VERSION 5.7 ;
  NOWIREEXTENSIONATPIN ON ;
  DIVIDERCHAR "/" ;
  BUSBITCHARS "[]" ;
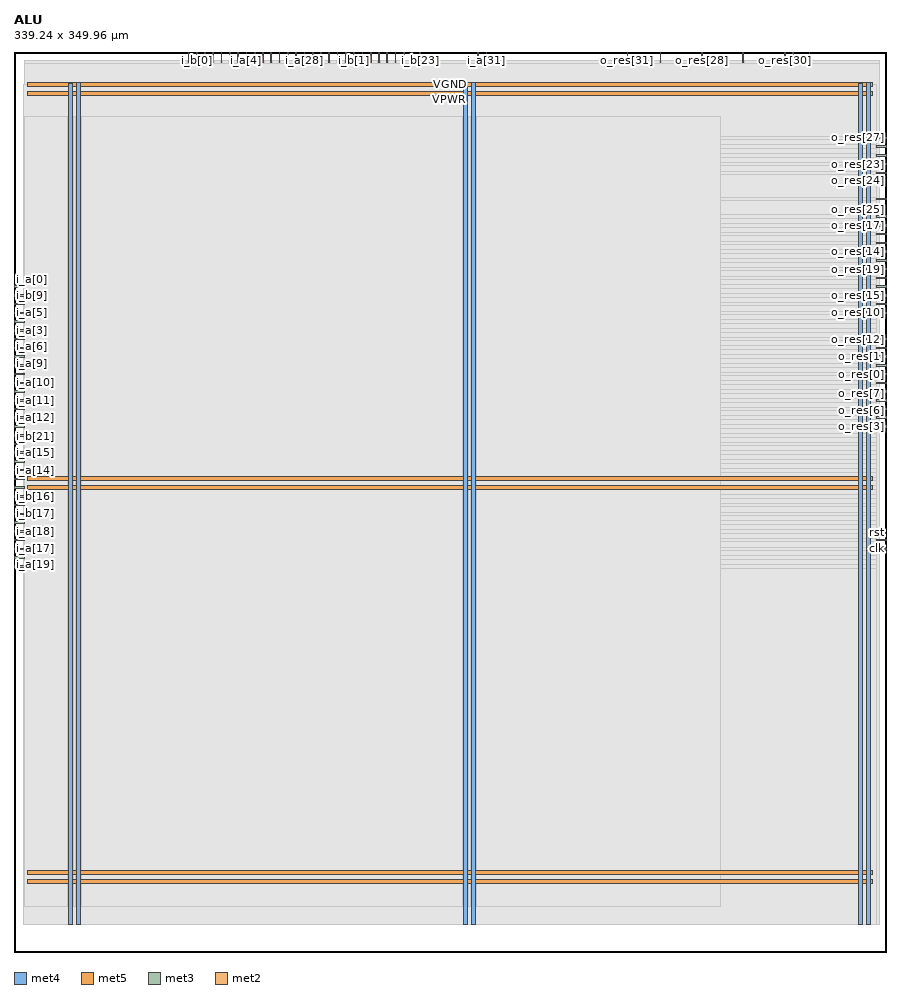
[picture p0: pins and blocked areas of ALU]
MACRO ALU
  CLASS BLOCK ;
  FOREIGN ALU ;
  ORIGIN 0.000 0.000 ;
  SIZE 339.240 BY 349.960 ;
  PIN VGND
    DIRECTION INOUT ;
    USE GROUND ;
    PORT
      LAYER met4 ;
        RECT 24.340 10.640 25.940 337.990 ;
    END
    PORT
      LAYER met4 ;
        RECT 177.940 10.640 179.540 337.990 ;
    END
    PORT
      LAYER met4 ;
        RECT 331.540 10.640 333.140 337.990 ;
    END
    PORT
      LAYER met5 ;
        RECT 5.280 30.030 333.740 31.630 ;
    END
    PORT
      LAYER met5 ;
        RECT 5.280 183.210 333.740 184.810 ;
    END
    PORT
      LAYER met5 ;
        RECT 5.280 336.390 333.740 337.990 ;
    END
  END VGND
  PIN VPWR
    DIRECTION INOUT ;
    USE POWER ;
    PORT
      LAYER met4 ;
        RECT 21.040 10.640 22.640 337.520 ;
    END
    PORT
      LAYER met4 ;
        RECT 174.640 10.640 176.240 337.520 ;
    END
    PORT
      LAYER met4 ;
        RECT 328.240 10.640 329.840 337.520 ;
    END
    PORT
      LAYER met5 ;
        RECT 5.280 26.730 333.740 28.330 ;
    END
    PORT
      LAYER met5 ;
        RECT 5.280 179.910 333.740 181.510 ;
    END
    PORT
      LAYER met5 ;
        RECT 5.280 333.090 333.740 334.690 ;
    END
  END VPWR
  PIN clk
    DIRECTION INPUT ;
    USE SIGNAL ;
    ANTENNAGATEAREA 0.852000 ;
    PORT
      LAYER met3 ;
        RECT 335.240 156.440 339.240 157.040 ;
    END
  END clk
  PIN i_a[0]
    DIRECTION INPUT ;
    USE SIGNAL ;
    ANTENNAGATEAREA 0.196500 ;
    PORT
      LAYER met3 ;
        RECT 0.000 258.440 4.000 259.040 ;
    END
  END i_a[0]
  PIN i_a[10]
    DIRECTION INPUT ;
    USE SIGNAL ;
    ANTENNAGATEAREA 0.196500 ;
    PORT
      LAYER met3 ;
        RECT 0.000 221.040 4.000 221.640 ;
    END
  END i_a[10]
  PIN i_a[11]
    DIRECTION INPUT ;
    USE SIGNAL ;
    ANTENNAGATEAREA 0.196500 ;
    PORT
      LAYER met3 ;
        RECT 0.000 214.240 4.000 214.840 ;
    END
  END i_a[11]
  PIN i_a[12]
    DIRECTION INPUT ;
    USE SIGNAL ;
    ANTENNAGATEAREA 0.196500 ;
    PORT
      LAYER met3 ;
        RECT 0.000 207.440 4.000 208.040 ;
    END
  END i_a[12]
  PIN i_a[13]
    DIRECTION INPUT ;
    USE SIGNAL ;
    ANTENNAGATEAREA 0.196500 ;
    PORT
      LAYER met3 ;
        RECT 0.000 200.640 4.000 201.240 ;
    END
  END i_a[13]
  PIN i_a[14]
    DIRECTION INPUT ;
    USE SIGNAL ;
    ANTENNAGATEAREA 0.196500 ;
    PORT
      LAYER met3 ;
        RECT 0.000 187.040 4.000 187.640 ;
    END
  END i_a[14]
  PIN i_a[15]
    DIRECTION INPUT ;
    USE SIGNAL ;
    ANTENNAGATEAREA 0.196500 ;
    PORT
      LAYER met3 ;
        RECT 0.000 193.840 4.000 194.440 ;
    END
  END i_a[15]
  PIN i_a[16]
    DIRECTION INPUT ;
    USE SIGNAL ;
    ANTENNAGATEAREA 0.196500 ;
    PORT
      LAYER met3 ;
        RECT 0.000 149.640 4.000 150.240 ;
    END
  END i_a[16]
  PIN i_a[17]
    DIRECTION INPUT ;
    USE SIGNAL ;
    ANTENNAGATEAREA 0.196500 ;
    PORT
      LAYER met3 ;
        RECT 0.000 156.440 4.000 157.040 ;
    END
  END i_a[17]
  PIN i_a[18]
    DIRECTION INPUT ;
    USE SIGNAL ;
    ANTENNAGATEAREA 0.196500 ;
    PORT
      LAYER met3 ;
        RECT 0.000 163.240 4.000 163.840 ;
    END
  END i_a[18]
  PIN i_a[19]
    DIRECTION INPUT ;
    USE SIGNAL ;
    ANTENNAGATEAREA 0.196500 ;
    PORT
      LAYER met3 ;
        RECT 0.000 153.040 4.000 153.640 ;
    END
  END i_a[19]
  PIN i_a[1]
    DIRECTION INPUT ;
    USE SIGNAL ;
    ANTENNAGATEAREA 0.196500 ;
    PORT
      LAYER met2 ;
        RECT 67.710 345.960 67.990 349.960 ;
    END
  END i_a[1]
  PIN i_a[20]
    DIRECTION INPUT ;
    USE SIGNAL ;
    ANTENNAGATEAREA 0.196500 ;
    PORT
      LAYER met3 ;
        RECT 0.000 183.640 4.000 184.240 ;
    END
  END i_a[20]
  PIN i_a[21]
    DIRECTION INPUT ;
    USE SIGNAL ;
    ANTENNAGATEAREA 0.196500 ;
    PORT
      LAYER met3 ;
        RECT 0.000 166.640 4.000 167.240 ;
    END
  END i_a[21]
  PIN i_a[22]
    DIRECTION INPUT ;
    USE SIGNAL ;
    ANTENNAGATEAREA 0.196500 ;
    PORT
      LAYER met3 ;
        RECT 0.000 159.840 4.000 160.440 ;
    END
  END i_a[22]
  PIN i_a[23]
    DIRECTION INPUT ;
    USE SIGNAL ;
    ANTENNAGATEAREA 0.196500 ;
    PORT
      LAYER met2 ;
        RECT 125.670 345.960 125.950 349.960 ;
    END
  END i_a[23]
  PIN i_a[24]
    DIRECTION INPUT ;
    USE SIGNAL ;
    ANTENNAGATEAREA 0.196500 ;
    PORT
      LAYER met2 ;
        RECT 122.450 345.960 122.730 349.960 ;
    END
  END i_a[24]
  PIN i_a[25]
    DIRECTION INPUT ;
    USE SIGNAL ;
    ANTENNAGATEAREA 0.196500 ;
    PORT
      LAYER met2 ;
        RECT 109.570 345.960 109.850 349.960 ;
    END
  END i_a[25]
  PIN i_a[26]
    DIRECTION INPUT ;
    USE SIGNAL ;
    ANTENNAGATEAREA 0.196500 ;
    PORT
      LAYER met2 ;
        RECT 119.230 345.960 119.510 349.960 ;
    END
  END i_a[26]
  PIN i_a[27]
    DIRECTION INPUT ;
    USE SIGNAL ;
    ANTENNAGATEAREA 0.196500 ;
    PORT
      LAYER met2 ;
        RECT 103.130 345.960 103.410 349.960 ;
    END
  END i_a[27]
  PIN i_a[28]
    DIRECTION INPUT ;
    USE SIGNAL ;
    ANTENNAGATEAREA 0.196500 ;
    PORT
      LAYER met2 ;
        RECT 112.790 345.960 113.070 349.960 ;
    END
  END i_a[28]
  PIN i_a[29]
    DIRECTION INPUT ;
    USE SIGNAL ;
    ANTENNAGATEAREA 0.196500 ;
    PORT
      LAYER met2 ;
        RECT 128.890 345.960 129.170 349.960 ;
    END
  END i_a[29]
  PIN i_a[2]
    DIRECTION INPUT ;
    USE SIGNAL ;
    ANTENNAGATEAREA 0.196500 ;
    PORT
      LAYER met2 ;
        RECT 83.810 345.960 84.090 349.960 ;
    END
  END i_a[2]
  PIN i_a[30]
    DIRECTION INPUT ;
    USE SIGNAL ;
    ANTENNAGATEAREA 0.196500 ;
    PORT
      LAYER met2 ;
        RECT 116.010 345.960 116.290 349.960 ;
    END
  END i_a[30]
  PIN i_a[31]
    DIRECTION INPUT ;
    USE SIGNAL ;
    ANTENNAGATEAREA 0.196500 ;
    PORT
      LAYER met2 ;
        RECT 183.630 345.960 183.910 349.960 ;
    END
  END i_a[31]
  PIN i_a[3]
    DIRECTION INPUT ;
    USE SIGNAL ;
    ANTENNAGATEAREA 0.196500 ;
    PORT
      LAYER met3 ;
        RECT 0.000 241.440 4.000 242.040 ;
    END
  END i_a[3]
  PIN i_a[4]
    DIRECTION INPUT ;
    USE SIGNAL ;
    ANTENNAGATEAREA 0.196500 ;
    PORT
      LAYER met2 ;
        RECT 90.250 345.960 90.530 349.960 ;
    END
  END i_a[4]
  PIN i_a[5]
    DIRECTION INPUT ;
    USE SIGNAL ;
    ANTENNAGATEAREA 0.196500 ;
    PORT
      LAYER met3 ;
        RECT 0.000 248.240 4.000 248.840 ;
    END
  END i_a[5]
  PIN i_a[6]
    DIRECTION INPUT ;
    USE SIGNAL ;
    ANTENNAGATEAREA 0.196500 ;
    PORT
      LAYER met3 ;
        RECT 0.000 238.040 4.000 238.640 ;
    END
  END i_a[6]
  PIN i_a[7]
    DIRECTION INPUT ;
    USE SIGNAL ;
    ANTENNAGATEAREA 0.196500 ;
    PORT
      LAYER met2 ;
        RECT 87.030 345.960 87.310 349.960 ;
    END
  END i_a[7]
  PIN i_a[8]
    DIRECTION INPUT ;
    USE SIGNAL ;
    ANTENNAGATEAREA 0.196500 ;
    PORT
      LAYER met3 ;
        RECT 0.000 234.640 4.000 235.240 ;
    END
  END i_a[8]
  PIN i_a[9]
    DIRECTION INPUT ;
    USE SIGNAL ;
    ANTENNAGATEAREA 0.196500 ;
    PORT
      LAYER met3 ;
        RECT 0.000 231.240 4.000 231.840 ;
    END
  END i_a[9]
  PIN i_b[0]
    DIRECTION INPUT ;
    USE SIGNAL ;
    ANTENNAGATEAREA 0.196500 ;
    PORT
      LAYER met2 ;
        RECT 70.930 345.960 71.210 349.960 ;
    END
  END i_b[0]
  PIN i_b[10]
    DIRECTION INPUT ;
    USE SIGNAL ;
    ANTENNAGATEAREA 0.196500 ;
    PORT
      LAYER met3 ;
        RECT 0.000 251.640 4.000 252.240 ;
    END
  END i_b[10]
  PIN i_b[11]
    DIRECTION INPUT ;
    USE SIGNAL ;
    ANTENNAGATEAREA 0.196500 ;
    PORT
      LAYER met3 ;
        RECT 0.000 244.840 4.000 245.440 ;
    END
  END i_b[11]
  PIN i_b[12]
    DIRECTION INPUT ;
    USE SIGNAL ;
    ANTENNAGATEAREA 0.196500 ;
    PORT
      LAYER met3 ;
        RECT 0.000 227.840 4.000 228.440 ;
    END
  END i_b[12]
  PIN i_b[13]
    DIRECTION INPUT ;
    USE SIGNAL ;
    ANTENNAGATEAREA 0.196500 ;
    PORT
      LAYER met3 ;
        RECT 0.000 224.440 4.000 225.040 ;
    END
  END i_b[13]
  PIN i_b[14]
    DIRECTION INPUT ;
    USE SIGNAL ;
    ANTENNAGATEAREA 0.196500 ;
    PORT
      LAYER met3 ;
        RECT 0.000 210.840 4.000 211.440 ;
    END
  END i_b[14]
  PIN i_b[15]
    DIRECTION INPUT ;
    USE SIGNAL ;
    ANTENNAGATEAREA 0.196500 ;
    PORT
      LAYER met3 ;
        RECT 0.000 217.640 4.000 218.240 ;
    END
  END i_b[15]
  PIN i_b[16]
    DIRECTION INPUT ;
    USE SIGNAL ;
    ANTENNAGATEAREA 0.196500 ;
    PORT
      LAYER met3 ;
        RECT 0.000 176.840 4.000 177.440 ;
    END
  END i_b[16]
  PIN i_b[17]
    DIRECTION INPUT ;
    USE SIGNAL ;
    ANTENNAGATEAREA 0.196500 ;
    PORT
      LAYER met3 ;
        RECT 0.000 170.040 4.000 170.640 ;
    END
  END i_b[17]
  PIN i_b[18]
    DIRECTION INPUT ;
    USE SIGNAL ;
    ANTENNAGATEAREA 0.196500 ;
    PORT
      LAYER met3 ;
        RECT 0.000 173.440 4.000 174.040 ;
    END
  END i_b[18]
  PIN i_b[19]
    DIRECTION INPUT ;
    USE SIGNAL ;
    ANTENNAGATEAREA 0.196500 ;
    PORT
      LAYER met3 ;
        RECT 0.000 180.240 4.000 180.840 ;
    END
  END i_b[19]
  PIN i_b[1]
    DIRECTION INPUT ;
    USE SIGNAL ;
    ANTENNAGATEAREA 0.196500 ;
    PORT
      LAYER met2 ;
        RECT 132.110 345.960 132.390 349.960 ;
    END
  END i_b[1]
  PIN i_b[20]
    DIRECTION INPUT ;
    USE SIGNAL ;
    ANTENNAGATEAREA 0.196500 ;
    PORT
      LAYER met3 ;
        RECT 0.000 190.440 4.000 191.040 ;
    END
  END i_b[20]
  PIN i_b[21]
    DIRECTION INPUT ;
    USE SIGNAL ;
    ANTENNAGATEAREA 0.196500 ;
    PORT
      LAYER met3 ;
        RECT 0.000 197.240 4.000 197.840 ;
    END
  END i_b[21]
  PIN i_b[22]
    DIRECTION INPUT ;
    USE SIGNAL ;
    ANTENNAGATEAREA 0.196500 ;
    PORT
      LAYER met3 ;
        RECT 0.000 204.040 4.000 204.640 ;
    END
  END i_b[22]
  PIN i_b[23]
    DIRECTION INPUT ;
    USE SIGNAL ;
    ANTENNAGATEAREA 0.196500 ;
    PORT
      LAYER met2 ;
        RECT 157.870 345.960 158.150 349.960 ;
    END
  END i_b[23]
  PIN i_b[24]
    DIRECTION INPUT ;
    USE SIGNAL ;
    ANTENNAGATEAREA 0.196500 ;
    PORT
      LAYER met2 ;
        RECT 151.430 345.960 151.710 349.960 ;
    END
  END i_b[24]
  PIN i_b[25]
    DIRECTION INPUT ;
    USE SIGNAL ;
    ANTENNAGATEAREA 0.196500 ;
    PORT
      LAYER met2 ;
        RECT 135.330 345.960 135.610 349.960 ;
    END
  END i_b[25]
  PIN i_b[26]
    DIRECTION INPUT ;
    USE SIGNAL ;
    ANTENNAGATEAREA 0.196500 ;
    PORT
      LAYER met2 ;
        RECT 148.210 345.960 148.490 349.960 ;
    END
  END i_b[26]
  PIN i_b[27]
    DIRECTION INPUT ;
    USE SIGNAL ;
    ANTENNAGATEAREA 0.196500 ;
    PORT
      LAYER met2 ;
        RECT 138.550 345.960 138.830 349.960 ;
    END
  END i_b[27]
  PIN i_b[28]
    DIRECTION INPUT ;
    USE SIGNAL ;
    ANTENNAGATEAREA 0.196500 ;
    PORT
      LAYER met2 ;
        RECT 154.650 345.960 154.930 349.960 ;
    END
  END i_b[28]
  PIN i_b[29]
    DIRECTION INPUT ;
    USE SIGNAL ;
    ANTENNAGATEAREA 0.196500 ;
    PORT
      LAYER met2 ;
        RECT 141.770 345.960 142.050 349.960 ;
    END
  END i_b[29]
  PIN i_b[2]
    DIRECTION INPUT ;
    USE SIGNAL ;
    ANTENNAGATEAREA 0.196500 ;
    PORT
      LAYER met2 ;
        RECT 106.350 345.960 106.630 349.960 ;
    END
  END i_b[2]
  PIN i_b[30]
    DIRECTION INPUT ;
    USE SIGNAL ;
    ANTENNAGATEAREA 0.196500 ;
    PORT
      LAYER met2 ;
        RECT 144.990 345.960 145.270 349.960 ;
    END
  END i_b[30]
  PIN i_b[31]
    DIRECTION INPUT ;
    USE SIGNAL ;
    ANTENNAGATEAREA 0.196500 ;
    PORT
      LAYER met2 ;
        RECT 180.410 345.960 180.690 349.960 ;
    END
  END i_b[31]
  PIN i_b[3]
    DIRECTION INPUT ;
    USE SIGNAL ;
    ANTENNAGATEAREA 0.196500 ;
    PORT
      LAYER met2 ;
        RECT 74.150 345.960 74.430 349.960 ;
    END
  END i_b[3]
  PIN i_b[4]
    DIRECTION INPUT ;
    USE SIGNAL ;
    ANTENNAGATEAREA 0.196500 ;
    PORT
      LAYER met2 ;
        RECT 96.690 345.960 96.970 349.960 ;
    END
  END i_b[4]
  PIN i_b[5]
    DIRECTION INPUT ;
    USE SIGNAL ;
    ANTENNAGATEAREA 0.196500 ;
    PORT
      LAYER met2 ;
        RECT 77.370 345.960 77.650 349.960 ;
    END
  END i_b[5]
  PIN i_b[6]
    DIRECTION INPUT ;
    USE SIGNAL ;
    ANTENNAGATEAREA 0.196500 ;
    PORT
      LAYER met2 ;
        RECT 99.910 345.960 100.190 349.960 ;
    END
  END i_b[6]
  PIN i_b[7]
    DIRECTION INPUT ;
    USE SIGNAL ;
    ANTENNAGATEAREA 0.196500 ;
    PORT
      LAYER met2 ;
        RECT 93.470 345.960 93.750 349.960 ;
    END
  END i_b[7]
  PIN i_b[8]
    DIRECTION INPUT ;
    USE SIGNAL ;
    ANTENNAGATEAREA 0.196500 ;
    PORT
      LAYER met2 ;
        RECT 80.590 345.960 80.870 349.960 ;
    END
  END i_b[8]
  PIN i_b[9]
    DIRECTION INPUT ;
    USE SIGNAL ;
    ANTENNAGATEAREA 0.196500 ;
    PORT
      LAYER met3 ;
        RECT 0.000 255.040 4.000 255.640 ;
    END
  END i_b[9]
  PIN i_vld
    DIRECTION INPUT ;
    USE SIGNAL ;
    ANTENNAGATEAREA 0.196500 ;
    PORT
      LAYER met2 ;
        RECT 302.770 345.960 303.050 349.960 ;
    END
  END i_vld
  PIN o_res[0]
    DIRECTION OUTPUT ;
    USE SIGNAL ;
    ANTENNADIFFAREA 0.445500 ;
    PORT
      LAYER met3 ;
        RECT 335.240 224.440 339.240 225.040 ;
    END
  END o_res[0]
  PIN o_res[10]
    DIRECTION OUTPUT ;
    USE SIGNAL ;
    ANTENNADIFFAREA 0.445500 ;
    PORT
      LAYER met3 ;
        RECT 335.240 248.240 339.240 248.840 ;
    END
  END o_res[10]
  PIN o_res[11]
    DIRECTION OUTPUT ;
    USE SIGNAL ;
    ANTENNADIFFAREA 0.445500 ;
    PORT
      LAYER met3 ;
        RECT 335.240 251.640 339.240 252.240 ;
    END
  END o_res[11]
  PIN o_res[12]
    DIRECTION OUTPUT ;
    USE SIGNAL ;
    ANTENNADIFFAREA 0.445500 ;
    PORT
      LAYER met3 ;
        RECT 335.240 238.040 339.240 238.640 ;
    END
  END o_res[12]
  PIN o_res[13]
    DIRECTION OUTPUT ;
    USE SIGNAL ;
    ANTENNADIFFAREA 0.445500 ;
    PORT
      LAYER met3 ;
        RECT 335.240 258.440 339.240 259.040 ;
    END
  END o_res[13]
  PIN o_res[14]
    DIRECTION OUTPUT ;
    USE SIGNAL ;
    ANTENNADIFFAREA 0.445500 ;
    PORT
      LAYER met3 ;
        RECT 335.240 272.040 339.240 272.640 ;
    END
  END o_res[14]
  PIN o_res[15]
    DIRECTION OUTPUT ;
    USE SIGNAL ;
    ANTENNADIFFAREA 0.445500 ;
    PORT
      LAYER met3 ;
        RECT 335.240 255.040 339.240 255.640 ;
    END
  END o_res[15]
  PIN o_res[16]
    DIRECTION OUTPUT ;
    USE SIGNAL ;
    ANTENNADIFFAREA 0.445500 ;
    PORT
      LAYER met3 ;
        RECT 335.240 261.840 339.240 262.440 ;
    END
  END o_res[16]
  PIN o_res[17]
    DIRECTION OUTPUT ;
    USE SIGNAL ;
    ANTENNADIFFAREA 0.445500 ;
    PORT
      LAYER met3 ;
        RECT 335.240 282.240 339.240 282.840 ;
    END
  END o_res[17]
  PIN o_res[18]
    DIRECTION OUTPUT ;
    USE SIGNAL ;
    ANTENNADIFFAREA 0.445500 ;
    PORT
      LAYER met3 ;
        RECT 335.240 275.440 339.240 276.040 ;
    END
  END o_res[18]
  PIN o_res[19]
    DIRECTION OUTPUT ;
    USE SIGNAL ;
    ANTENNADIFFAREA 0.445500 ;
    PORT
      LAYER met3 ;
        RECT 335.240 265.240 339.240 265.840 ;
    END
  END o_res[19]
  PIN o_res[1]
    DIRECTION OUTPUT ;
    USE SIGNAL ;
    ANTENNADIFFAREA 0.445500 ;
    PORT
      LAYER met3 ;
        RECT 335.240 231.240 339.240 231.840 ;
    END
  END o_res[1]
  PIN o_res[20]
    DIRECTION OUTPUT ;
    USE SIGNAL ;
    ANTENNADIFFAREA 0.445500 ;
    PORT
      LAYER met3 ;
        RECT 335.240 278.840 339.240 279.440 ;
    END
  END o_res[20]
  PIN o_res[21]
    DIRECTION OUTPUT ;
    USE SIGNAL ;
    ANTENNADIFFAREA 0.445500 ;
    PORT
      LAYER met3 ;
        RECT 335.240 268.640 339.240 269.240 ;
    END
  END o_res[21]
  PIN o_res[22]
    DIRECTION OUTPUT ;
    USE SIGNAL ;
    ANTENNADIFFAREA 0.445500 ;
    PORT
      LAYER met2 ;
        RECT 283.450 345.960 283.730 349.960 ;
    END
  END o_res[22]
  PIN o_res[23]
    DIRECTION OUTPUT ;
    USE SIGNAL ;
    ANTENNADIFFAREA 0.445500 ;
    PORT
      LAYER met3 ;
        RECT 335.240 306.040 339.240 306.640 ;
    END
  END o_res[23]
  PIN o_res[24]
    DIRECTION OUTPUT ;
    USE SIGNAL ;
    ANTENNADIFFAREA 0.445500 ;
    PORT
      LAYER met3 ;
        RECT 335.240 302.640 339.240 303.240 ;
    END
  END o_res[24]
  PIN o_res[25]
    DIRECTION OUTPUT ;
    USE SIGNAL ;
    ANTENNADIFFAREA 0.445500 ;
    PORT
      LAYER met3 ;
        RECT 335.240 285.640 339.240 286.240 ;
    END
  END o_res[25]
  PIN o_res[26]
    DIRECTION OUTPUT ;
    USE SIGNAL ;
    ANTENNADIFFAREA 0.445500 ;
    PORT
      LAYER met3 ;
        RECT 335.240 292.440 339.240 293.040 ;
    END
  END o_res[26]
  PIN o_res[27]
    DIRECTION OUTPUT ;
    USE SIGNAL ;
    ANTENNADIFFAREA 0.445500 ;
    PORT
      LAYER met3 ;
        RECT 335.240 316.240 339.240 316.840 ;
    END
  END o_res[27]
  PIN o_res[28]
    DIRECTION OUTPUT ;
    USE SIGNAL ;
    ANTENNADIFFAREA 0.445500 ;
    PORT
      LAYER met2 ;
        RECT 267.350 345.960 267.630 349.960 ;
    END
  END o_res[28]
  PIN o_res[29]
    DIRECTION OUTPUT ;
    USE SIGNAL ;
    ANTENNADIFFAREA 0.445500 ;
    PORT
      LAYER met2 ;
        RECT 251.250 345.960 251.530 349.960 ;
    END
  END o_res[29]
  PIN o_res[2]
    DIRECTION OUTPUT ;
    USE SIGNAL ;
    ANTENNADIFFAREA 0.445500 ;
    PORT
      LAYER met3 ;
        RECT 335.240 234.640 339.240 235.240 ;
    END
  END o_res[2]
  PIN o_res[30]
    DIRECTION OUTPUT ;
    USE SIGNAL ;
    ANTENNADIFFAREA 0.445500 ;
    PORT
      LAYER met2 ;
        RECT 299.550 345.960 299.830 349.960 ;
    END
  END o_res[30]
  PIN o_res[31]
    DIRECTION OUTPUT ;
    USE SIGNAL ;
    ANTENNADIFFAREA 0.445500 ;
    PORT
      LAYER met2 ;
        RECT 238.370 345.960 238.650 349.960 ;
    END
  END o_res[31]
  PIN o_res[3]
    DIRECTION OUTPUT ;
    USE SIGNAL ;
    ANTENNADIFFAREA 0.445500 ;
    PORT
      LAYER met3 ;
        RECT 335.240 204.040 339.240 204.640 ;
    END
  END o_res[3]
  PIN o_res[4]
    DIRECTION OUTPUT ;
    USE SIGNAL ;
    ANTENNADIFFAREA 0.445500 ;
    PORT
      LAYER met3 ;
        RECT 335.240 227.840 339.240 228.440 ;
    END
  END o_res[4]
  PIN o_res[5]
    DIRECTION OUTPUT ;
    USE SIGNAL ;
    ANTENNADIFFAREA 0.445500 ;
    PORT
      LAYER met3 ;
        RECT 335.240 217.640 339.240 218.240 ;
    END
  END o_res[5]
  PIN o_res[6]
    DIRECTION OUTPUT ;
    USE SIGNAL ;
    ANTENNADIFFAREA 0.445500 ;
    PORT
      LAYER met3 ;
        RECT 335.240 207.440 339.240 208.040 ;
    END
  END o_res[6]
  PIN o_res[7]
    DIRECTION OUTPUT ;
    USE SIGNAL ;
    ANTENNADIFFAREA 0.445500 ;
    PORT
      LAYER met3 ;
        RECT 335.240 214.240 339.240 214.840 ;
    END
  END o_res[7]
  PIN o_res[8]
    DIRECTION OUTPUT ;
    USE SIGNAL ;
    ANTENNADIFFAREA 0.445500 ;
    PORT
      LAYER met3 ;
        RECT 335.240 210.840 339.240 211.440 ;
    END
  END o_res[8]
  PIN o_res[9]
    DIRECTION OUTPUT ;
    USE SIGNAL ;
    ANTENNADIFFAREA 0.445500 ;
    PORT
      LAYER met3 ;
        RECT 335.240 221.040 339.240 221.640 ;
    END
  END o_res[9]
  PIN o_res_vld
    DIRECTION OUTPUT ;
    USE SIGNAL ;
    ANTENNADIFFAREA 0.445500 ;
    PORT
      LAYER met3 ;
        RECT 335.240 309.440 339.240 310.040 ;
    END
  END o_res_vld
  PIN opcode
    DIRECTION INPUT ;
    USE SIGNAL ;
    ANTENNAGATEAREA 0.196500 ;
    PORT
      LAYER met3 ;
        RECT 335.240 312.840 339.240 313.440 ;
    END
  END opcode
  PIN overflow
    DIRECTION OUTPUT ;
    USE SIGNAL ;
    ANTENNADIFFAREA 0.445500 ;
    PORT
      LAYER met2 ;
        RECT 309.210 345.960 309.490 349.960 ;
    END
  END overflow
  PIN rst
    DIRECTION INPUT ;
    USE SIGNAL ;
    ANTENNAGATEAREA 0.196500 ;
    PORT
      LAYER met3 ;
        RECT 335.240 159.840 339.240 160.440 ;
    END
  END rst
  OBS
      LAYER nwell ;
        RECT 5.330 10.795 333.690 337.365 ;
      LAYER li1 ;
        RECT 5.520 10.795 333.500 337.365 ;
      LAYER met1 ;
        RECT 4.210 10.640 336.650 338.200 ;
      LAYER met2 ;
        RECT 4.230 345.680 67.430 346.530 ;
        RECT 68.270 345.680 70.650 346.530 ;
        RECT 71.490 345.680 73.870 346.530 ;
        RECT 74.710 345.680 77.090 346.530 ;
        RECT 77.930 345.680 80.310 346.530 ;
        RECT 81.150 345.680 83.530 346.530 ;
        RECT 84.370 345.680 86.750 346.530 ;
        RECT 87.590 345.680 89.970 346.530 ;
        RECT 90.810 345.680 93.190 346.530 ;
        RECT 94.030 345.680 96.410 346.530 ;
        RECT 97.250 345.680 99.630 346.530 ;
        RECT 100.470 345.680 102.850 346.530 ;
        RECT 103.690 345.680 106.070 346.530 ;
        RECT 106.910 345.680 109.290 346.530 ;
        RECT 110.130 345.680 112.510 346.530 ;
        RECT 113.350 345.680 115.730 346.530 ;
        RECT 116.570 345.680 118.950 346.530 ;
        RECT 119.790 345.680 122.170 346.530 ;
        RECT 123.010 345.680 125.390 346.530 ;
        RECT 126.230 345.680 128.610 346.530 ;
        RECT 129.450 345.680 131.830 346.530 ;
        RECT 132.670 345.680 135.050 346.530 ;
        RECT 135.890 345.680 138.270 346.530 ;
        RECT 139.110 345.680 141.490 346.530 ;
        RECT 142.330 345.680 144.710 346.530 ;
        RECT 145.550 345.680 147.930 346.530 ;
        RECT 148.770 345.680 151.150 346.530 ;
        RECT 151.990 345.680 154.370 346.530 ;
        RECT 155.210 345.680 157.590 346.530 ;
        RECT 158.430 345.680 180.130 346.530 ;
        RECT 180.970 345.680 183.350 346.530 ;
        RECT 184.190 345.680 238.090 346.530 ;
        RECT 238.930 345.680 250.970 346.530 ;
        RECT 251.810 345.680 267.070 346.530 ;
        RECT 267.910 345.680 283.170 346.530 ;
        RECT 284.010 345.680 299.270 346.530 ;
        RECT 300.110 345.680 302.490 346.530 ;
        RECT 303.330 345.680 308.930 346.530 ;
        RECT 309.770 345.680 336.620 346.530 ;
        RECT 4.230 10.695 336.620 345.680 ;
      LAYER met3 ;
        RECT 3.750 317.240 335.240 337.445 ;
        RECT 3.750 315.840 334.840 317.240 ;
        RECT 3.750 313.840 335.240 315.840 ;
        RECT 3.750 312.440 334.840 313.840 ;
        RECT 3.750 310.440 335.240 312.440 ;
        RECT 3.750 309.040 334.840 310.440 ;
        RECT 3.750 307.040 335.240 309.040 ;
        RECT 3.750 305.640 334.840 307.040 ;
        RECT 3.750 303.640 335.240 305.640 ;
        RECT 3.750 302.240 334.840 303.640 ;
        RECT 3.750 293.440 335.240 302.240 ;
        RECT 3.750 292.040 334.840 293.440 ;
        RECT 3.750 286.640 335.240 292.040 ;
        RECT 3.750 285.240 334.840 286.640 ;
        RECT 3.750 283.240 335.240 285.240 ;
        RECT 3.750 281.840 334.840 283.240 ;
        RECT 3.750 279.840 335.240 281.840 ;
        RECT 3.750 278.440 334.840 279.840 ;
        RECT 3.750 276.440 335.240 278.440 ;
        RECT 3.750 275.040 334.840 276.440 ;
        RECT 3.750 273.040 335.240 275.040 ;
        RECT 3.750 271.640 334.840 273.040 ;
        RECT 3.750 269.640 335.240 271.640 ;
        RECT 3.750 268.240 334.840 269.640 ;
        RECT 3.750 266.240 335.240 268.240 ;
        RECT 3.750 264.840 334.840 266.240 ;
        RECT 3.750 262.840 335.240 264.840 ;
        RECT 3.750 261.440 334.840 262.840 ;
        RECT 3.750 259.440 335.240 261.440 ;
        RECT 4.400 258.040 334.840 259.440 ;
        RECT 3.750 256.040 335.240 258.040 ;
        RECT 4.400 254.640 334.840 256.040 ;
        RECT 3.750 252.640 335.240 254.640 ;
        RECT 4.400 251.240 334.840 252.640 ;
        RECT 3.750 249.240 335.240 251.240 ;
        RECT 4.400 247.840 334.840 249.240 ;
        RECT 3.750 245.840 335.240 247.840 ;
        RECT 4.400 244.440 335.240 245.840 ;
        RECT 3.750 242.440 335.240 244.440 ;
        RECT 4.400 241.040 335.240 242.440 ;
        RECT 3.750 239.040 335.240 241.040 ;
        RECT 4.400 237.640 334.840 239.040 ;
        RECT 3.750 235.640 335.240 237.640 ;
        RECT 4.400 234.240 334.840 235.640 ;
        RECT 3.750 232.240 335.240 234.240 ;
        RECT 4.400 230.840 334.840 232.240 ;
        RECT 3.750 228.840 335.240 230.840 ;
        RECT 4.400 227.440 334.840 228.840 ;
        RECT 3.750 225.440 335.240 227.440 ;
        RECT 4.400 224.040 334.840 225.440 ;
        RECT 3.750 222.040 335.240 224.040 ;
        RECT 4.400 220.640 334.840 222.040 ;
        RECT 3.750 218.640 335.240 220.640 ;
        RECT 4.400 217.240 334.840 218.640 ;
        RECT 3.750 215.240 335.240 217.240 ;
        RECT 4.400 213.840 334.840 215.240 ;
        RECT 3.750 211.840 335.240 213.840 ;
        RECT 4.400 210.440 334.840 211.840 ;
        RECT 3.750 208.440 335.240 210.440 ;
        RECT 4.400 207.040 334.840 208.440 ;
        RECT 3.750 205.040 335.240 207.040 ;
        RECT 4.400 203.640 334.840 205.040 ;
        RECT 3.750 201.640 335.240 203.640 ;
        RECT 4.400 200.240 335.240 201.640 ;
        RECT 3.750 198.240 335.240 200.240 ;
        RECT 4.400 196.840 335.240 198.240 ;
        RECT 3.750 194.840 335.240 196.840 ;
        RECT 4.400 193.440 335.240 194.840 ;
        RECT 3.750 191.440 335.240 193.440 ;
        RECT 4.400 190.040 335.240 191.440 ;
        RECT 3.750 188.040 335.240 190.040 ;
        RECT 4.400 186.640 335.240 188.040 ;
        RECT 3.750 184.640 335.240 186.640 ;
        RECT 4.400 183.240 335.240 184.640 ;
        RECT 3.750 181.240 335.240 183.240 ;
        RECT 4.400 179.840 335.240 181.240 ;
        RECT 3.750 177.840 335.240 179.840 ;
        RECT 4.400 176.440 335.240 177.840 ;
        RECT 3.750 174.440 335.240 176.440 ;
        RECT 4.400 173.040 335.240 174.440 ;
        RECT 3.750 171.040 335.240 173.040 ;
        RECT 4.400 169.640 335.240 171.040 ;
        RECT 3.750 167.640 335.240 169.640 ;
        RECT 4.400 166.240 335.240 167.640 ;
        RECT 3.750 164.240 335.240 166.240 ;
        RECT 4.400 162.840 335.240 164.240 ;
        RECT 3.750 160.840 335.240 162.840 ;
        RECT 4.400 159.440 334.840 160.840 ;
        RECT 3.750 157.440 335.240 159.440 ;
        RECT 4.400 156.040 334.840 157.440 ;
        RECT 3.750 154.040 335.240 156.040 ;
        RECT 4.400 152.640 335.240 154.040 ;
        RECT 3.750 150.640 335.240 152.640 ;
        RECT 4.400 149.240 335.240 150.640 ;
        RECT 3.750 10.715 335.240 149.240 ;
      LAYER met4 ;
        RECT 3.975 17.855 20.640 324.865 ;
        RECT 23.040 17.855 23.940 324.865 ;
        RECT 26.340 17.855 174.240 324.865 ;
        RECT 176.640 17.855 177.540 324.865 ;
        RECT 179.940 17.855 274.785 324.865 ;
  END
END ALU
END LIBRARY

